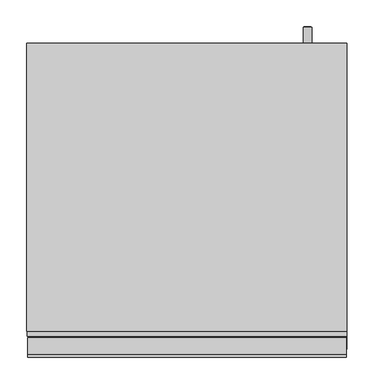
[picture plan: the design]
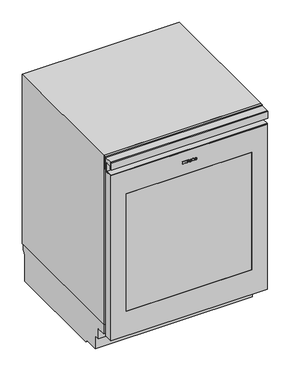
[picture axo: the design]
"""IFC4 building model written with IfcOpenShell, lengths in millimetres: proxy geometry."""

from ifc_helpers import new_model, si_unit, point, frame, frame_2d, origin, origin_with_axes, place, context, project, spatial, polyline, circle_curve, ellipse_curve, trimmed, segment, composite_curve, outline, extrude, faceted_brep, source, transform, mapped, element, save
from ifc_brep_helpers import plane_surface, cylinder_surface, revolved_surface, extruded_surface, advanced_brep


def specialty_equipment_1184f20f(model_context):
    return source(origin(), model_context, "Body", "SolidModel", [
        extrude(outline(polyline([(722.339, -25.038), (722.339, -23.949), (716.318, -23.949), (716.318, -25.038), (714.806, -25.038), (714.806, -21.078), (716.318, -21.078), (716.318, -22.158), (720.1401247, -22.158), (714.806, -18.135), (720.2462223, -14.094), (716.318, -14.094), (716.318, -15.201), (714.806, -15.201), (714.806, -8.019), (716.318, -8.019), (716.318, -9.162), (722.339, -9.162), (722.339, -8.019), (723.806, -8.019), (723.806, -13.5), (720.431, -16.128), (723.806, -18.765), (723.806, -25.038), (722.339, -25.038)])), frame((0.0, -1.0, 0.0), z_axis=(0.0, 1.0, 0.0), x_axis=(0.0, 0.0, 1.0)), (0.0, 0.0, 1.0), 1.0),
        extrude(outline(polyline([(722.339, 11.484), (722.339, 12.564), (716.318, 12.564), (716.318, 11.484), (714.806, 11.484), (714.806, 18.783), (716.318, 18.783), (716.318, 17.676), (723.806, 17.676), (723.806, 11.484), (722.339, 11.484)])), frame((0.0, -1.0, 0.0), z_axis=(0.0, 1.0, 0.0), x_axis=(0.0, 0.0, 1.0)), (0.0, 0.0, 1.0), 1.0),
        extrude(outline(polyline([(723.275, -4.878), (721.817, -4.194), (723.239, -1.143), (724.697, -1.818), (723.275, -4.878)])), frame((0.0, -1.0, 0.0), z_axis=(0.0, 1.0, 0.0), x_axis=(0.0, 0.0, 1.0)), (0.0, 0.0, 1.0), 1.0),
        extrude(outline(polyline([(721.619, -7.101), (720.008, -7.101), (720.008, -6.03), (716.318, -6.03), (716.318, -7.101), (714.806, -7.101), (714.806, 0.0), (716.318, 0.0), (716.318, -1.044), (721.619, -1.044), (721.619, -7.101)])), frame((0.0, -1.0, 0.0), z_axis=(0.0, 1.0, 0.0), x_axis=(0.0, 0.0, 1.0)), (0.0, 0.0, 1.0), 1.0),
        advanced_brep(
        [(4.959, -1.0, 716.939), (4.959, -1.0, 717.848), (10.98, -1.0, 717.848), (0.504, -1.0, 717.848), (2.979, -1.0, 714.806), (10.827, -1.0, 716.939), (8.109, -1.0, 716.939), (5.967, -1.0, 715.931), (4.959, -1.0, 719.0), (4.959, -1.0, 719.981), (6.498, -1.0, 719.981), (6.498, -1.0, 719.0), (4.959, 0.0, 716.939), (5.967, 0.0, 715.931), (8.109, 0.0, 716.939), (10.827, 0.0, 716.939), (2.979, 0.0, 714.806), (0.504, 0.0, 717.848), (10.98, 0.0, 717.848), (4.959, 0.0, 717.848), (4.959, 0.0, 719.0), (6.498, 0.0, 719.0), (6.498, 0.0, 719.981), (4.959, 0.0, 719.981)],
        [
            (0, 1),
            (1, 2),
            (2, 3, ellipse_curve(frame((5.742, -1.0, 717.848), z_axis=(0.0, -1.0, 0.0), x_axis=(-1.0, 0.0, 0.0)), 5.238, 4.329)),
            (3, 4, circle_curve(frame((3.9870491, -1.0, 718.154), z_axis=(0.0, -1.0, 0.0), x_axis=(0.0, 0.0, -1.0)), 3.4964649)),
            (4, 5, circle_curve(frame((5.6371428, -1.0, 720.53), z_axis=(0.0, -1.0, 0.0), x_axis=(0.0, 0.0, -1.0)), 6.3110933)),
            (5, 6),
            (6, 7, circle_curve(frame((6.4069412, -1.0, 717.776), z_axis=(0.0, 1.0, 0.0), x_axis=(0.0, 0.0, -1.0)), 1.896727)),
            (7, 0, circle_curve(frame((5.967, -1.0, 716.939), z_axis=(0.0, 1.0, 0.0), x_axis=(0.0, 0.0, -1.0)), 1.008)),
            (8, 9),
            (9, 10, circle_curve(frame((5.7285, -1.0, 719.981), z_axis=(0.0, 1.0, 0.0), x_axis=(0.0, 0.0, -1.0)), 0.7695)),
            (10, 11),
            (11, 8),
            (12, 13, circle_curve(frame((5.967, 0.0, 716.939), z_axis=(0.0, -1.0, 0.0), x_axis=(0.0, 0.0, -1.0)), 1.008)),
            (13, 14, circle_curve(frame((6.4069412, 0.0, 717.776), z_axis=(0.0, -1.0, 0.0), x_axis=(0.0, 0.0, -1.0)), 1.896727)),
            (14, 15),
            (15, 16, circle_curve(frame((5.6371428, 0.0, 720.53), z_axis=(0.0, 1.0, 0.0), x_axis=(0.0, 0.0, -1.0)), 6.3110933)),
            (16, 17, circle_curve(frame((3.9870491, 0.0, 718.154), z_axis=(0.0, 1.0, 0.0), x_axis=(0.0, 0.0, -1.0)), 3.4964649)),
            (17, 18, ellipse_curve(frame((5.742, 0.0, 717.848), z_axis=(0.0, 1.0, 0.0), x_axis=(-1.0, 0.0, 0.0)), 5.238, 4.329)),
            (18, 19),
            (19, 12),
            (20, 21),
            (21, 22),
            (22, 23, circle_curve(frame((5.7285, 0.0, 719.981), z_axis=(0.0, -1.0, 0.0), x_axis=(0.0, 0.0, -1.0)), 0.7695)),
            (23, 20),
            (0, 12),
            (19, 1),
            (18, 2),
            (5, 15),
            (14, 6),
            (17, 3),
            (13, 7),
            (16, 4),
            (8, 20),
            (23, 9),
            (22, 10),
            (21, 11),
        ],
        [
            plane_surface(frame((4.959, -1.0, 717.848), z_axis=(0.0, -1.0, 0.0), x_axis=(0.0, 0.0, 1.0))),
            plane_surface(frame((4.959, 0.0, 717.848), z_axis=(0.0, 1.0, 0.0), x_axis=(0.0, 0.0, -1.0))),
            plane_surface(frame((4.959, -1.0, 716.939), z_axis=(1.0, 0.0, 0.0), x_axis=(0.0, 1.0, 0.0))),
            plane_surface(frame((4.959, -1.0, 717.848), z_axis=(0.0, 0.0, -1.0), x_axis=(0.0, 1.0, 0.0))),
            plane_surface(frame((10.827, -1.0, 716.939), z_axis=(0.0, 0.0, 1.0), x_axis=(0.0, 1.0, 0.0))),
            extruded_surface(trimmed(ellipse_curve(frame((5.742, 1.0, 717.848), z_axis=(0.0, -1.0, 0.0), x_axis=(-1.0, 0.0, 0.0)), 5.238, 4.329), [point((10.98, 1.0, 717.848))], [point((0.504, 1.0, 717.848))], True, "CARTESIAN"), (0.0, -1.0, 0.0), 1.0),
            revolved_surface(polyline([(6.4069412, 0.0, 715.8792729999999), (6.4069412, -1.0, 715.8792729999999)]), (6.4069412, 0.0, 717.776), (0.0, 1.0, 0.0)),
            revolved_surface(polyline([(5.967, 0.0, 715.9309999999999), (5.967, -1.0, 715.9309999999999)]), (5.967, 0.0, 716.939), (0.0, 1.0, 0.0)),
            cylinder_surface(frame((3.9870491, 0.0, 718.154), z_axis=(0.0, -1.0, 0.0), x_axis=(0.0, 0.0, -1.0)), 3.4964649),
            cylinder_surface(frame((5.6371428, 0.0, 720.53), z_axis=(0.0, -1.0, 0.0), x_axis=(0.0, 0.0, -1.0)), 6.3110933),
            plane_surface(frame((4.959, -1.0, 719.0), z_axis=(1.0, 0.0, 0.0), x_axis=(0.0, 1.0, 0.0))),
            revolved_surface(polyline([(5.7285, 0.0, 719.2115), (5.7285, -1.0, 719.2115)]), (5.7285, 0.0, 719.981), (0.0, 1.0, 0.0)),
            plane_surface(frame((6.498, -1.0, 719.981), z_axis=(-1.0, 0.0, 0.0), x_axis=(0.0, 1.0, 0.0))),
            plane_surface(frame((6.498, -1.0, 719.0), z_axis=(0.0, 0.0, 1.0), x_axis=(0.0, 1.0, 0.0))),
        ],
        [
            (0, [[1, 2, 3, 4, 5, 6, 7, 8], [9, 10, 11, 12]]),
            (1, [[13, 14, 15, 16, 17, 18, 19, 20], [21, 22, 23, 24]]),
            (2, [[-1, 25, -20, 26]]),
            (3, [[-2, -26, -19, 27]]),
            (4, [[-6, 28, -15, 29]]),
            (5, [[-3, -27, -18, 30]]),
            (6, [[-7, -29, -14, 31]]),
            (7, [[-8, -31, -13, -25]]),
            (8, [[-4, -30, -17, 32]]),
            (9, [[-5, -32, -16, -28]]),
            (10, [[-9, 33, -24, 34]]),
            (11, [[-10, -34, -23, 35]]),
            (12, [[-11, -35, -22, 36]]),
            (13, [[-12, -36, -21, -33]]),
        ],
    ),
        advanced_brep(
        [(23.742, -1.0, 716.939), (23.742, -1.0, 717.848), (29.763, -1.0, 717.848), (19.287, -1.0, 717.848), (21.762, -1.0, 714.806), (29.61, -1.0, 716.939), (26.892, -1.0, 716.939), (24.75, -1.0, 715.931), (23.742, -1.0, 719.0), (23.742, -1.0, 719.981), (25.281, -1.0, 719.981), (25.281, -1.0, 719.0), (23.742, 0.0, 716.939), (24.75, 0.0, 715.931), (26.892, 0.0, 716.939), (29.61, 0.0, 716.939), (21.762, 0.0, 714.806), (19.287, 0.0, 717.848), (29.763, 0.0, 717.848), (23.742, 0.0, 717.848), (23.742, 0.0, 719.0), (25.281, 0.0, 719.0), (25.281, 0.0, 719.981), (23.742, 0.0, 719.981)],
        [
            (0, 1),
            (1, 2),
            (2, 3, ellipse_curve(frame((24.525, -1.0, 717.848), z_axis=(0.0, -1.0, 0.0), x_axis=(-1.0, 0.0, 0.0)), 5.238, 4.329)),
            (3, 4, circle_curve(frame((22.7700491, -1.0, 718.154), z_axis=(0.0, -1.0, 0.0), x_axis=(0.0, 0.0, -1.0)), 3.4964649)),
            (4, 5, circle_curve(frame((24.4201428, -1.0, 720.53), z_axis=(0.0, -1.0, 0.0), x_axis=(0.0, 0.0, -1.0)), 6.3110933)),
            (5, 6),
            (6, 7, circle_curve(frame((25.1899412, -1.0, 717.776), z_axis=(0.0, 1.0, 0.0), x_axis=(0.0, 0.0, -1.0)), 1.896727)),
            (7, 0, circle_curve(frame((24.75, -1.0, 716.939), z_axis=(0.0, 1.0, 0.0), x_axis=(0.0, 0.0, -1.0)), 1.008)),
            (8, 9),
            (9, 10, circle_curve(frame((24.5115, -1.0, 719.981), z_axis=(0.0, 1.0, 0.0), x_axis=(0.0, 0.0, -1.0)), 0.7695)),
            (10, 11),
            (11, 8),
            (12, 13, circle_curve(frame((24.75, 0.0, 716.939), z_axis=(0.0, -1.0, 0.0), x_axis=(0.0, 0.0, -1.0)), 1.008)),
            (13, 14, circle_curve(frame((25.1899412, 0.0, 717.776), z_axis=(0.0, -1.0, 0.0), x_axis=(0.0, 0.0, -1.0)), 1.896727)),
            (14, 15),
            (15, 16, circle_curve(frame((24.4201428, 0.0, 720.53), z_axis=(0.0, 1.0, 0.0), x_axis=(0.0, 0.0, -1.0)), 6.3110933)),
            (16, 17, circle_curve(frame((22.7700491, 0.0, 718.154), z_axis=(0.0, 1.0, 0.0), x_axis=(0.0, 0.0, -1.0)), 3.4964649)),
            (17, 18, ellipse_curve(frame((24.525, 0.0, 717.848), z_axis=(0.0, 1.0, 0.0), x_axis=(-1.0, 0.0, 0.0)), 5.238, 4.329)),
            (18, 19),
            (19, 12),
            (20, 21),
            (21, 22),
            (22, 23, circle_curve(frame((24.5115, 0.0, 719.981), z_axis=(0.0, -1.0, 0.0), x_axis=(0.0, 0.0, -1.0)), 0.7695)),
            (23, 20),
            (0, 12),
            (19, 1),
            (18, 2),
            (5, 15),
            (14, 6),
            (17, 3),
            (13, 7),
            (16, 4),
            (8, 20),
            (23, 9),
            (22, 10),
            (21, 11),
        ],
        [
            plane_surface(frame((23.742, -1.0, 717.848), z_axis=(0.0, -1.0, 0.0), x_axis=(0.0, 0.0, 1.0))),
            plane_surface(frame((23.742, 0.0, 717.848), z_axis=(0.0, 1.0, 0.0), x_axis=(0.0, 0.0, -1.0))),
            plane_surface(frame((23.742, -1.0, 716.939), z_axis=(1.0, 0.0, 0.0), x_axis=(0.0, 1.0, 0.0))),
            plane_surface(frame((23.742, -1.0, 717.848), z_axis=(0.0, 0.0, -1.0), x_axis=(0.0, 1.0, 0.0))),
            plane_surface(frame((29.61, -1.0, 716.939), z_axis=(0.0, 0.0, 1.0), x_axis=(0.0, 1.0, 0.0))),
            extruded_surface(trimmed(ellipse_curve(frame((24.525, 1.0, 717.848), z_axis=(0.0, -1.0, 0.0), x_axis=(-1.0, 0.0, 0.0)), 5.238, 4.329), [point((29.763, 1.0, 717.848))], [point((19.287, 1.0, 717.848))], True, "CARTESIAN"), (0.0, -1.0, 0.0), 1.0),
            revolved_surface(polyline([(25.1899412, 0.0, 715.8792729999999), (25.1899412, -1.0, 715.8792729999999)]), (25.1899412, 0.0, 717.776), (0.0, 1.0, 0.0)),
            revolved_surface(polyline([(24.75, 0.0, 715.9309999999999), (24.75, -1.0, 715.9309999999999)]), (24.75, 0.0, 716.939), (0.0, 1.0, 0.0)),
            cylinder_surface(frame((22.7700491, 0.0, 718.154), z_axis=(0.0, -1.0, 0.0), x_axis=(0.0, 0.0, -1.0)), 3.4964649),
            cylinder_surface(frame((24.4201428, 0.0, 720.53), z_axis=(0.0, -1.0, 0.0), x_axis=(0.0, 0.0, -1.0)), 6.3110933),
            plane_surface(frame((23.742, -1.0, 719.0), z_axis=(1.0, 0.0, 0.0), x_axis=(0.0, 1.0, 0.0))),
            revolved_surface(polyline([(24.5115, 0.0, 719.2115), (24.5115, -1.0, 719.2115)]), (24.5115, 0.0, 719.981), (0.0, 1.0, 0.0)),
            plane_surface(frame((25.281, -1.0, 719.981), z_axis=(-1.0, 0.0, 0.0), x_axis=(0.0, 1.0, 0.0))),
            plane_surface(frame((25.281, -1.0, 719.0), z_axis=(0.0, 0.0, 1.0), x_axis=(0.0, 1.0, 0.0))),
        ],
        [
            (0, [[1, 2, 3, 4, 5, 6, 7, 8], [9, 10, 11, 12]]),
            (1, [[13, 14, 15, 16, 17, 18, 19, 20], [21, 22, 23, 24]]),
            (2, [[-1, 25, -20, 26]]),
            (3, [[-2, -26, -19, 27]]),
            (4, [[-6, 28, -15, 29]]),
            (5, [[-3, -27, -18, 30]]),
            (6, [[-7, -29, -14, 31]]),
            (7, [[-8, -31, -13, -25]]),
            (8, [[-4, -30, -17, 32]]),
            (9, [[-5, -32, -16, -28]]),
            (10, [[-9, 33, -24, 34]]),
            (11, [[-10, -34, -23, 35]]),
            (12, [[-11, -35, -22, 36]]),
            (13, [[-12, -36, -21, -33]]),
        ],
    ),
        extrude(outline(polyline([(699.491, -85.038), (699.491, -83.949), (693.47, -83.949), (693.47, -85.038), (691.958, -85.038), (691.958, -81.078), (693.47, -81.078), (693.47, -82.158), (697.2921247, -82.158), (691.958, -78.135), (697.3982223, -74.094), (693.47, -74.094), (693.47, -75.201), (691.958, -75.201), (691.958, -68.019), (693.47, -68.019), (693.47, -69.162), (699.491, -69.162), (699.491, -68.019), (700.958, -68.019), (700.958, -73.5), (697.583, -76.128), (700.958, -78.765), (700.958, -85.038), (699.491, -85.038)])), frame((0.0, 50.0, 0.0), z_axis=(0.0, 1.0, 0.0), x_axis=(0.0, 0.0, 1.0)), (0.0, 0.0, 1.0), 1.0),
        extrude(outline(polyline([(699.491, -48.516), (699.491, -47.436), (693.47, -47.436), (693.47, -48.516), (691.958, -48.516), (691.958, -41.217), (693.47, -41.217), (693.47, -42.324), (700.958, -42.324), (700.958, -48.516), (699.491, -48.516)])), frame((0.0, 50.0, 0.0), z_axis=(0.0, 1.0, 0.0), x_axis=(0.0, 0.0, 1.0)), (0.0, 0.0, 1.0), 1.0),
        extrude(outline(polyline([(700.427, -64.878), (698.969, -64.194), (700.391, -61.143), (701.849, -61.818), (700.427, -64.878)])), frame((0.0, 50.0, 0.0), z_axis=(0.0, 1.0, 0.0), x_axis=(0.0, 0.0, 1.0)), (0.0, 0.0, 1.0), 1.0),
        extrude(outline(polyline([(698.771, -67.101), (697.16, -67.101), (697.16, -66.03), (693.47, -66.03), (693.47, -67.101), (691.958, -67.101), (691.958, -60.0), (693.47, -60.0), (693.47, -61.044), (698.771, -61.044), (698.771, -67.101)])), frame((0.0, 50.0, 0.0), z_axis=(0.0, 1.0, 0.0), x_axis=(0.0, 0.0, 1.0)), (0.0, 0.0, 1.0), 1.0),
        advanced_brep(
        [(-55.041, 50.0, 694.091), (-55.041, 50.0, 695.0), (-49.02, 50.0, 695.0), (-59.496, 50.0, 695.0), (-57.021, 50.0, 691.958), (-49.173, 50.0, 694.091), (-51.891, 50.0, 694.091), (-54.033, 50.0, 693.083), (-55.041, 50.0, 696.152), (-55.041, 50.0, 697.133), (-53.502, 50.0, 697.133), (-53.502, 50.0, 696.152), (-55.041, 51.0, 694.091), (-54.033, 51.0, 693.083), (-51.891, 51.0, 694.091), (-49.173, 51.0, 694.091), (-57.021, 51.0, 691.958), (-59.496, 51.0, 695.0), (-49.02, 51.0, 695.0), (-55.041, 51.0, 695.0), (-55.041, 51.0, 696.152), (-53.502, 51.0, 696.152), (-53.502, 51.0, 697.133), (-55.041, 51.0, 697.133)],
        [
            (0, 1),
            (1, 2),
            (2, 3, ellipse_curve(frame((-54.258, 50.0, 695.0), z_axis=(0.0, -1.0, 0.0), x_axis=(-1.0, 0.0, 0.0)), 5.238, 4.329)),
            (3, 4, circle_curve(frame((-56.0129509, 50.0, 695.306), z_axis=(0.0, -1.0, 0.0), x_axis=(0.0, 0.0, -1.0)), 3.4964649)),
            (4, 5, circle_curve(frame((-54.3628572, 50.0, 697.682), z_axis=(0.0, -1.0, 0.0), x_axis=(0.0, 0.0, -1.0)), 6.3110933)),
            (5, 6),
            (6, 7, circle_curve(frame((-53.5930588, 50.0, 694.928), z_axis=(0.0, 1.0, 0.0), x_axis=(0.0, 0.0, -1.0)), 1.896727)),
            (7, 0, circle_curve(frame((-54.033, 50.0, 694.091), z_axis=(0.0, 1.0, 0.0), x_axis=(0.0, 0.0, -1.0)), 1.008)),
            (8, 9),
            (9, 10, circle_curve(frame((-54.2715, 50.0, 697.133), z_axis=(0.0, 1.0, 0.0), x_axis=(0.0, 0.0, -1.0)), 0.7695)),
            (10, 11),
            (11, 8),
            (12, 13, circle_curve(frame((-54.033, 51.0, 694.091), z_axis=(0.0, -1.0, 0.0), x_axis=(0.0, 0.0, -1.0)), 1.008)),
            (13, 14, circle_curve(frame((-53.5930588, 51.0, 694.928), z_axis=(0.0, -1.0, 0.0), x_axis=(0.0, 0.0, -1.0)), 1.896727)),
            (14, 15),
            (15, 16, circle_curve(frame((-54.3628572, 51.0, 697.682), z_axis=(0.0, 1.0, 0.0), x_axis=(0.0, 0.0, -1.0)), 6.3110933)),
            (16, 17, circle_curve(frame((-56.0129509, 51.0, 695.306), z_axis=(0.0, 1.0, 0.0), x_axis=(0.0, 0.0, -1.0)), 3.4964649)),
            (17, 18, ellipse_curve(frame((-54.258, 51.0, 695.0), z_axis=(0.0, 1.0, 0.0), x_axis=(-1.0, 0.0, 0.0)), 5.238, 4.329)),
            (18, 19),
            (19, 12),
            (20, 21),
            (21, 22),
            (22, 23, circle_curve(frame((-54.2715, 51.0, 697.133), z_axis=(0.0, -1.0, 0.0), x_axis=(0.0, 0.0, -1.0)), 0.7695)),
            (23, 20),
            (0, 12),
            (19, 1),
            (18, 2),
            (5, 15),
            (14, 6),
            (17, 3),
            (13, 7),
            (16, 4),
            (8, 20),
            (23, 9),
            (22, 10),
            (21, 11),
        ],
        [
            plane_surface(frame((-55.041, 50.0, 695.0), z_axis=(0.0, -1.0, 0.0), x_axis=(0.0, 0.0, 1.0))),
            plane_surface(frame((-55.041, 51.0, 695.0), z_axis=(0.0, 1.0, 0.0), x_axis=(0.0, 0.0, -1.0))),
            plane_surface(frame((-55.041, 50.0, 694.091), z_axis=(1.0, 0.0, 0.0), x_axis=(0.0, 1.0, 0.0))),
            plane_surface(frame((-55.041, 50.0, 695.0), z_axis=(0.0, 0.0, -1.0), x_axis=(0.0, 1.0, 0.0))),
            plane_surface(frame((-49.173, 50.0, 694.091), z_axis=(0.0, 0.0, 1.0), x_axis=(0.0, 1.0, 0.0))),
            extruded_surface(trimmed(ellipse_curve(frame((-54.258, 52.0, 695.0), z_axis=(0.0, -1.0, 0.0), x_axis=(-1.0, 0.0, 0.0)), 5.238, 4.329), [point((-49.02, 52.0, 695.0))], [point((-59.496, 52.0, 695.0))], True, "CARTESIAN"), (0.0, -1.0, 0.0), 1.0),
            revolved_surface(polyline([(-53.5930588, 51.0, 693.0312729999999), (-53.5930588, 50.0, 693.0312729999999)]), (-53.5930588, 51.0, 694.928), (0.0, 1.0, 0.0)),
            revolved_surface(polyline([(-54.033, 51.0, 693.083), (-54.033, 50.0, 693.083)]), (-54.033, 51.0, 694.091), (0.0, 1.0, 0.0)),
            cylinder_surface(frame((-56.0129509, 51.0, 695.306), z_axis=(0.0, -1.0, 0.0), x_axis=(0.0, 0.0, -1.0)), 3.4964649),
            cylinder_surface(frame((-54.3628572, 51.0, 697.682), z_axis=(0.0, -1.0, 0.0), x_axis=(0.0, 0.0, -1.0)), 6.3110933),
            plane_surface(frame((-55.041, 50.0, 696.152), z_axis=(1.0, 0.0, 0.0), x_axis=(0.0, 1.0, 0.0))),
            revolved_surface(polyline([(-54.2715, 51.0, 696.3635), (-54.2715, 50.0, 696.3635)]), (-54.2715, 51.0, 697.133), (0.0, 1.0, 0.0)),
            plane_surface(frame((-53.502, 50.0, 697.133), z_axis=(-1.0, 0.0, 0.0), x_axis=(0.0, 1.0, 0.0))),
            plane_surface(frame((-53.502, 50.0, 696.152), z_axis=(0.0, 0.0, 1.0), x_axis=(0.0, 1.0, 0.0))),
        ],
        [
            (0, [[1, 2, 3, 4, 5, 6, 7, 8], [9, 10, 11, 12]]),
            (1, [[13, 14, 15, 16, 17, 18, 19, 20], [21, 22, 23, 24]]),
            (2, [[-1, 25, -20, 26]]),
            (3, [[-2, -26, -19, 27]]),
            (4, [[-6, 28, -15, 29]]),
            (5, [[-3, -27, -18, 30]]),
            (6, [[-7, -29, -14, 31]]),
            (7, [[-8, -31, -13, -25]]),
            (8, [[-4, -30, -17, 32]]),
            (9, [[-5, -32, -16, -28]]),
            (10, [[-9, 33, -24, 34]]),
            (11, [[-10, -34, -23, 35]]),
            (12, [[-11, -35, -22, 36]]),
            (13, [[-12, -36, -21, -33]]),
        ],
    ),
        advanced_brep(
        [(-36.258, 50.0, 694.091), (-36.258, 50.0, 695.0), (-30.237, 50.0, 695.0), (-40.713, 50.0, 695.0), (-38.238, 50.0, 691.958), (-30.39, 50.0, 694.091), (-33.108, 50.0, 694.091), (-35.25, 50.0, 693.083), (-36.258, 50.0, 696.152), (-36.258, 50.0, 697.133), (-34.719, 50.0, 697.133), (-34.719, 50.0, 696.152), (-36.258, 51.0, 694.091), (-35.25, 51.0, 693.083), (-33.108, 51.0, 694.091), (-30.39, 51.0, 694.091), (-38.238, 51.0, 691.958), (-40.713, 51.0, 695.0), (-30.237, 51.0, 695.0), (-36.258, 51.0, 695.0), (-36.258, 51.0, 696.152), (-34.719, 51.0, 696.152), (-34.719, 51.0, 697.133), (-36.258, 51.0, 697.133)],
        [
            (0, 1),
            (1, 2),
            (2, 3, ellipse_curve(frame((-35.475, 50.0, 695.0), z_axis=(0.0, -1.0, 0.0), x_axis=(-1.0, 0.0, 0.0)), 5.238, 4.329)),
            (3, 4, circle_curve(frame((-37.2299509, 50.0, 695.306), z_axis=(0.0, -1.0, 0.0), x_axis=(0.0, 0.0, -1.0)), 3.4964649)),
            (4, 5, circle_curve(frame((-35.5798572, 50.0, 697.682), z_axis=(0.0, -1.0, 0.0), x_axis=(0.0, 0.0, -1.0)), 6.3110933)),
            (5, 6),
            (6, 7, circle_curve(frame((-34.8100588, 50.0, 694.928), z_axis=(0.0, 1.0, 0.0), x_axis=(0.0, 0.0, -1.0)), 1.896727)),
            (7, 0, circle_curve(frame((-35.25, 50.0, 694.091), z_axis=(0.0, 1.0, 0.0), x_axis=(0.0, 0.0, -1.0)), 1.008)),
            (8, 9),
            (9, 10, circle_curve(frame((-35.4885, 50.0, 697.133), z_axis=(0.0, 1.0, 0.0), x_axis=(0.0, 0.0, -1.0)), 0.7695)),
            (10, 11),
            (11, 8),
            (12, 13, circle_curve(frame((-35.25, 51.0, 694.091), z_axis=(0.0, -1.0, 0.0), x_axis=(0.0, 0.0, -1.0)), 1.008)),
            (13, 14, circle_curve(frame((-34.8100588, 51.0, 694.928), z_axis=(0.0, -1.0, 0.0), x_axis=(0.0, 0.0, -1.0)), 1.896727)),
            (14, 15),
            (15, 16, circle_curve(frame((-35.5798572, 51.0, 697.682), z_axis=(0.0, 1.0, 0.0), x_axis=(0.0, 0.0, -1.0)), 6.3110933)),
            (16, 17, circle_curve(frame((-37.2299509, 51.0, 695.306), z_axis=(0.0, 1.0, 0.0), x_axis=(0.0, 0.0, -1.0)), 3.4964649)),
            (17, 18, ellipse_curve(frame((-35.475, 51.0, 695.0), z_axis=(0.0, 1.0, 0.0), x_axis=(-1.0, 0.0, 0.0)), 5.238, 4.329)),
            (18, 19),
            (19, 12),
            (20, 21),
            (21, 22),
            (22, 23, circle_curve(frame((-35.4885, 51.0, 697.133), z_axis=(0.0, -1.0, 0.0), x_axis=(0.0, 0.0, -1.0)), 0.7695)),
            (23, 20),
            (0, 12),
            (19, 1),
            (18, 2),
            (5, 15),
            (14, 6),
            (17, 3),
            (13, 7),
            (16, 4),
            (8, 20),
            (23, 9),
            (22, 10),
            (21, 11),
        ],
        [
            plane_surface(frame((-36.258, 50.0, 695.0), z_axis=(0.0, -1.0, 0.0), x_axis=(0.0, 0.0, 1.0))),
            plane_surface(frame((-36.258, 51.0, 695.0), z_axis=(0.0, 1.0, 0.0), x_axis=(0.0, 0.0, -1.0))),
            plane_surface(frame((-36.258, 50.0, 694.091), z_axis=(1.0, 0.0, 0.0), x_axis=(0.0, 1.0, 0.0))),
            plane_surface(frame((-36.258, 50.0, 695.0), z_axis=(0.0, 0.0, -1.0), x_axis=(0.0, 1.0, 0.0))),
            plane_surface(frame((-30.39, 50.0, 694.091), z_axis=(0.0, 0.0, 1.0), x_axis=(0.0, 1.0, 0.0))),
            extruded_surface(trimmed(ellipse_curve(frame((-35.475, 52.0, 695.0), z_axis=(0.0, -1.0, 0.0), x_axis=(-1.0, 0.0, 0.0)), 5.238, 4.329), [point((-30.237, 52.0, 695.0))], [point((-40.713, 52.0, 695.0))], True, "CARTESIAN"), (0.0, -1.0, 0.0), 1.0),
            revolved_surface(polyline([(-34.8100588, 51.0, 693.0312729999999), (-34.8100588, 50.0, 693.0312729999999)]), (-34.8100588, 51.0, 694.928), (0.0, 1.0, 0.0)),
            revolved_surface(polyline([(-35.25, 51.0, 693.083), (-35.25, 50.0, 693.083)]), (-35.25, 51.0, 694.091), (0.0, 1.0, 0.0)),
            cylinder_surface(frame((-37.2299509, 51.0, 695.306), z_axis=(0.0, -1.0, 0.0), x_axis=(0.0, 0.0, -1.0)), 3.4964649),
            cylinder_surface(frame((-35.5798572, 51.0, 697.682), z_axis=(0.0, -1.0, 0.0), x_axis=(0.0, 0.0, -1.0)), 6.3110933),
            plane_surface(frame((-36.258, 50.0, 696.152), z_axis=(1.0, 0.0, 0.0), x_axis=(0.0, 1.0, 0.0))),
            revolved_surface(polyline([(-35.4885, 51.0, 696.3635), (-35.4885, 50.0, 696.3635)]), (-35.4885, 51.0, 697.133), (0.0, 1.0, 0.0)),
            plane_surface(frame((-34.719, 50.0, 697.133), z_axis=(-1.0, 0.0, 0.0), x_axis=(0.0, 1.0, 0.0))),
            plane_surface(frame((-34.719, 50.0, 696.152), z_axis=(0.0, 0.0, 1.0), x_axis=(0.0, 1.0, 0.0))),
        ],
        [
            (0, [[1, 2, 3, 4, 5, 6, 7, 8], [9, 10, 11, 12]]),
            (1, [[13, 14, 15, 16, 17, 18, 19, 20], [21, 22, 23, 24]]),
            (2, [[-1, 25, -20, 26]]),
            (3, [[-2, -26, -19, 27]]),
            (4, [[-6, 28, -15, 29]]),
            (5, [[-3, -27, -18, 30]]),
            (6, [[-7, -29, -14, 31]]),
            (7, [[-8, -31, -13, -25]]),
            (8, [[-4, -30, -17, 32]]),
            (9, [[-5, -32, -16, -28]]),
            (10, [[-9, 33, -24, 34]]),
            (11, [[-10, -34, -23, 35]]),
            (12, [[-11, -35, -22, 36]]),
            (13, [[-12, -36, -21, -33]]),
        ],
    ),
        extrude(outline(polyline([(567.7947388, -157.5), (572.5, -157.5), (576.5, -161.5), (576.5, -168.5), (572.5, -172.5), (567.7947388, -172.5), (567.7947388, -157.5)])), frame((0.0, 54.5000244, 0.0), z_axis=(0.0, 1.0, 0.0), x_axis=(0.0, 0.0, 1.0)), (0.0, 0.0, 1.0), 433.111792),
        extrude(outline(polyline([(567.7947388, -102.5), (572.5, -102.5), (576.5, -106.5), (576.5, -113.5), (572.5, -117.5), (567.7947388, -117.5), (567.7947388, -102.5)])), frame((0.0, 54.5000244, 0.0), z_axis=(0.0, 1.0, 0.0), x_axis=(0.0, 0.0, 1.0)), (0.0, 0.0, 1.0), 433.111792),
        extrude(outline(polyline([(567.7947388, 157.5), (567.7947388, 172.5), (572.5, 172.5), (576.5, 168.5), (576.5, 161.5), (572.5, 157.5), (567.7947388, 157.5)])), frame((0.0, 54.5000244, 0.0), z_axis=(0.0, 1.0, 0.0), x_axis=(0.0, 0.0, 1.0)), (0.0, 0.0, 1.0), 433.111792),
        extrude(outline(polyline([(567.7947388, 102.5), (567.7947388, 117.5), (572.5, 117.5), (576.5, 113.5), (576.5, 106.5), (572.5, 102.5), (567.7947388, 102.5)])), frame((0.0, 54.5000244, 0.0), z_axis=(0.0, 1.0, 0.0), x_axis=(0.0, 0.0, 1.0)), (0.0, 0.0, 1.0), 433.111792),
        extrude(outline(polyline([(567.7947388, -47.5), (572.5, -47.5), (576.5, -51.5), (576.5, -58.5), (572.5, -62.5), (567.7947388, -62.5), (567.7947388, -47.5)])), frame((0.0, 54.5000244, 0.0), z_axis=(0.0, 1.0, 0.0), x_axis=(0.0, 0.0, 1.0)), (0.0, 0.0, 1.0), 433.111792),
        extrude(outline(polyline([(567.7947388, 47.5), (567.7947388, 62.5), (572.5, 62.5), (576.5, 58.5), (576.5, 51.5), (572.5, 47.5), (567.7947388, 47.5)])), frame((0.0, 54.5000244, 0.0), z_axis=(0.0, 1.0, 0.0), x_axis=(0.0, 0.0, 1.0)), (0.0, 0.0, 1.0), 433.111792),
        extrude(outline(polyline([(567.7947388, 7.5), (572.5, 7.5), (576.5, 3.5), (576.5, -3.5), (572.5, -7.5), (567.7947388, -7.5), (567.7947388, 7.5)])), frame((0.0, 54.5000244, 0.0), z_axis=(0.0, 1.0, 0.0), x_axis=(0.0, 0.0, 1.0)), (0.0, 0.0, 1.0), 433.111792),
        extrude(outline(polyline([(478.3, -157.5), (483.0052612, -157.5), (487.0052612, -161.5), (487.0052612, -168.5), (483.0052612, -172.5), (478.3, -172.5), (478.3, -157.5)])), frame((0.0, 54.5000244, 0.0), z_axis=(0.0, 1.0, 0.0), x_axis=(0.0, 0.0, 1.0)), (0.0, 0.0, 1.0), 433.111792),
        extrude(outline(polyline([(478.3, -102.5), (483.0052612, -102.5), (487.0052612, -106.5), (487.0052612, -113.5), (483.0052612, -117.5), (478.3, -117.5), (478.3, -102.5)])), frame((0.0, 54.5000244, 0.0), z_axis=(0.0, 1.0, 0.0), x_axis=(0.0, 0.0, 1.0)), (0.0, 0.0, 1.0), 433.111792),
        extrude(outline(polyline([(478.3, 157.5), (478.3, 172.5), (483.0052612, 172.5), (487.0052612, 168.5), (487.0052612, 161.5), (483.0052612, 157.5), (478.3, 157.5)])), frame((0.0, 54.5000244, 0.0), z_axis=(0.0, 1.0, 0.0), x_axis=(0.0, 0.0, 1.0)), (0.0, 0.0, 1.0), 433.111792),
        extrude(outline(polyline([(478.3, 102.5), (478.3, 117.5), (483.0052612, 117.5), (487.0052612, 113.5), (487.0052612, 106.5), (483.0052612, 102.5), (478.3, 102.5)])), frame((0.0, 54.5000244, 0.0), z_axis=(0.0, 1.0, 0.0), x_axis=(0.0, 0.0, 1.0)), (0.0, 0.0, 1.0), 433.111792),
        extrude(outline(polyline([(478.3, -47.5), (483.0052612, -47.5), (487.0052612, -51.5), (487.0052612, -58.5), (483.0052612, -62.5), (478.3, -62.5), (478.3, -47.5)])), frame((0.0, 54.5000244, 0.0), z_axis=(0.0, 1.0, 0.0), x_axis=(0.0, 0.0, 1.0)), (0.0, 0.0, 1.0), 433.111792),
        extrude(outline(polyline([(478.3, 47.5), (478.3, 62.5), (483.0052612, 62.5), (487.0052612, 58.5), (487.0052612, 51.5), (483.0052612, 47.5), (478.3, 47.5)])), frame((0.0, 54.5000244, 0.0), z_axis=(0.0, 1.0, 0.0), x_axis=(0.0, 0.0, 1.0)), (0.0, 0.0, 1.0), 433.111792),
        extrude(outline(polyline([(478.3, 7.5), (483.0052612, 7.5), (487.0052612, 3.5), (487.0052612, -3.5), (483.0052612, -7.5), (478.3, -7.5), (478.3, 7.5)])), frame((0.0, 54.5000244, 0.0), z_axis=(0.0, 1.0, 0.0), x_axis=(0.0, 0.0, 1.0)), (0.0, 0.0, 1.0), 433.111792),
        extrude(outline(polyline([(387.8, -157.5), (392.5052612, -157.5), (396.5052612, -161.5), (396.5052612, -168.5), (392.5052612, -172.5), (387.8, -172.5), (387.8, -157.5)])), frame((0.0, 54.5000244, 0.0), z_axis=(0.0, 1.0, 0.0), x_axis=(0.0, 0.0, 1.0)), (0.0, 0.0, 1.0), 433.111792),
        extrude(outline(polyline([(387.8, -102.5), (392.5052612, -102.5), (396.5052612, -106.5), (396.5052612, -113.5), (392.5052612, -117.5), (387.8, -117.5), (387.8, -102.5)])), frame((0.0, 54.5000244, 0.0), z_axis=(0.0, 1.0, 0.0), x_axis=(0.0, 0.0, 1.0)), (0.0, 0.0, 1.0), 433.111792),
        extrude(outline(polyline([(387.8, 157.5), (387.8, 172.5), (392.5052612, 172.5), (396.5052612, 168.5), (396.5052612, 161.5), (392.5052612, 157.5), (387.8, 157.5)])), frame((0.0, 54.5000244, 0.0), z_axis=(0.0, 1.0, 0.0), x_axis=(0.0, 0.0, 1.0)), (0.0, 0.0, 1.0), 433.111792),
        extrude(outline(polyline([(387.8, 102.5), (387.8, 117.5), (392.5052612, 117.5), (396.5052612, 113.5), (396.5052612, 106.5), (392.5052612, 102.5), (387.8, 102.5)])), frame((0.0, 54.5000244, 0.0), z_axis=(0.0, 1.0, 0.0), x_axis=(0.0, 0.0, 1.0)), (0.0, 0.0, 1.0), 433.111792),
        extrude(outline(polyline([(387.8, -47.5), (392.5052612, -47.5), (396.5052612, -51.5), (396.5052612, -58.5), (392.5052612, -62.5), (387.8, -62.5), (387.8, -47.5)])), frame((0.0, 54.5000244, 0.0), z_axis=(0.0, 1.0, 0.0), x_axis=(0.0, 0.0, 1.0)), (0.0, 0.0, 1.0), 433.111792),
        extrude(outline(polyline([(387.8, 47.5), (387.8, 62.5), (392.5052612, 62.5), (396.5052612, 58.5), (396.5052612, 51.5), (392.5052612, 47.5), (387.8, 47.5)])), frame((0.0, 54.5000244, 0.0), z_axis=(0.0, 1.0, 0.0), x_axis=(0.0, 0.0, 1.0)), (0.0, 0.0, 1.0), 433.111792),
        extrude(outline(polyline([(387.8, 7.5), (392.5052612, 7.5), (396.5052612, 3.5), (396.5052612, -3.5), (392.5052612, -7.5), (387.8, -7.5), (387.8, 7.5)])), frame((0.0, 54.5000244, 0.0), z_axis=(0.0, 1.0, 0.0), x_axis=(0.0, 0.0, 1.0)), (0.0, 0.0, 1.0), 433.111792),
        extrude(outline(polyline([(238.8, -157.5), (243.5052612, -157.5), (247.5052612, -161.5), (247.5052612, -168.5), (243.5052612, -172.5), (238.8, -172.5), (238.8, -157.5)])), frame((0.0, 54.5000244, 0.0), z_axis=(0.0, 1.0, 0.0), x_axis=(0.0, 0.0, 1.0)), (0.0, 0.0, 1.0), 433.111792),
        extrude(outline(polyline([(238.8, -102.5), (243.5052612, -102.5), (247.5052612, -106.5), (247.5052612, -113.5), (243.5052612, -117.5), (238.8, -117.5), (238.8, -102.5)])), frame((0.0, 54.5000244, 0.0), z_axis=(0.0, 1.0, 0.0), x_axis=(0.0, 0.0, 1.0)), (0.0, 0.0, 1.0), 433.111792),
        extrude(outline(polyline([(238.8, 157.5), (238.8, 172.5), (243.5052612, 172.5), (247.5052612, 168.5), (247.5052612, 161.5), (243.5052612, 157.5), (238.8, 157.5)])), frame((0.0, 54.5000244, 0.0), z_axis=(0.0, 1.0, 0.0), x_axis=(0.0, 0.0, 1.0)), (0.0, 0.0, 1.0), 433.111792),
        extrude(outline(polyline([(238.8, 102.5), (238.8, 117.5), (243.5052612, 117.5), (247.5052612, 113.5), (247.5052612, 106.5), (243.5052612, 102.5), (238.8, 102.5)])), frame((0.0, 54.5000244, 0.0), z_axis=(0.0, 1.0, 0.0), x_axis=(0.0, 0.0, 1.0)), (0.0, 0.0, 1.0), 433.111792),
        extrude(outline(polyline([(238.8, -47.5), (243.5052612, -47.5), (247.5052612, -51.5), (247.5052612, -58.5), (243.5052612, -62.5), (238.8, -62.5), (238.8, -47.5)])), frame((0.0, 54.5000244, 0.0), z_axis=(0.0, 1.0, 0.0), x_axis=(0.0, 0.0, 1.0)), (0.0, 0.0, 1.0), 433.111792),
        extrude(outline(polyline([(238.8, 47.5), (238.8, 62.5), (243.5052612, 62.5), (247.5052612, 58.5), (247.5052612, 51.5), (243.5052612, 47.5), (238.8, 47.5)])), frame((0.0, 54.5000244, 0.0), z_axis=(0.0, 1.0, 0.0), x_axis=(0.0, 0.0, 1.0)), (0.0, 0.0, 1.0), 433.111792),
        extrude(outline(polyline([(238.8, 7.5), (243.5052612, 7.5), (247.5052612, 3.5), (247.5052612, -3.5), (243.5052612, -7.5), (238.8, -7.5), (238.8, 7.5)])), frame((0.0, 54.5000244, 0.0), z_axis=(0.0, 1.0, 0.0), x_axis=(0.0, 0.0, 1.0)), (0.0, 0.0, 1.0), 433.111792),
        extrude(outline(polyline([(238.5, 51.0000244), (-238.5, 51.0000244), (-238.5, 54.5000244), (238.5, 54.5000244), (238.5, 51.0000244)])), frame((0.0, 0.0, 146.0), z_axis=(0.0, 0.0, 1.0), x_axis=(1.0, 0.0, 0.0)), (0.0, 0.0, 1.0), 27.5),
        extrude(outline(polyline([(238.5, 51.0000244), (-238.5, 51.0000244), (-238.5, 54.5000244), (238.5, 54.5000244), (238.5, 51.0000244)])), frame((0.0, 0.0, 235.0), z_axis=(0.0, 0.0, 1.0), x_axis=(1.0, 0.0, 0.0)), (0.0, 0.0, 1.0), 27.5),
        extrude(outline(polyline([(209.0, -226.9226475), (209.0, -238.5), (141.0206134, -238.5), (141.0206134, -216.8069153), (191.4790485, -216.8069153), (209.0, -226.9226475)])), frame((0.0, 54.5000244, 0.0), z_axis=(0.0, 1.0, 0.0), x_axis=(0.0, 0.0, 1.0)), (0.0, 0.0, 1.0), 308.1981801),
        extrude(outline(polyline([(209.0, 226.9226475), (191.4790485, 216.8069153), (141.0206134, 216.8069153), (141.0206134, 238.5), (209.0, 238.5), (209.0, 226.9226475)])), frame((0.0, 54.5000244, 0.0), z_axis=(0.0, 1.0, 0.0), x_axis=(0.0, 0.0, 1.0)), (0.0, 0.0, 1.0), 308.1981801),
        extrude(outline(polyline([(238.5, 51.0000244), (-238.5, 51.0000244), (-238.5, 54.5000244), (238.5, 54.5000244), (238.5, 51.0000244)])), frame((0.0, 0.0, 564.0), z_axis=(0.0, 0.0, 1.0), x_axis=(1.0, 0.0, 0.0)), (0.0, 0.0, 1.0), 27.5),
        extrude(outline(polyline([(238.5, 51.0000244), (-238.5, 51.0000244), (-238.5, 54.5000244), (238.5, 54.5000244), (238.5, 51.0000244)])), frame((0.0, 0.0, 474.5), z_axis=(0.0, 0.0, 1.0), x_axis=(1.0, 0.0, 0.0)), (0.0, 0.0, 1.0), 27.5),
        extrude(outline(polyline([(238.5, 51.0000244), (-238.5, 51.0000244), (-238.5, 54.5000244), (238.5, 54.5000244), (238.5, 51.0000244)])), frame((0.0, 0.0, 384.0), z_axis=(0.0, 0.0, 1.0), x_axis=(1.0, 0.0, 0.0)), (0.0, 0.0, 1.0), 27.5),
        faceted_brep([(250.0, 51.0000244, 719.0), (-250.0, 51.0000244, 719.0), (-250.0, 51.0000244, 665.5838574), (250.0, 51.0000244, 665.5838574), (24.4663125, 51.0000244, 676.4573822), (-24.4663125, 51.0000244, 676.4573822), (-24.4663125, 51.0000244, 712.8698491), (24.4663125, 51.0000244, 712.8698491), (250.0, 487.6118164, 719.0), (250.0, 487.6118164, 665.5838574), (-250.0, 487.6118164, 665.5838574), (-250.0, 487.6118164, 719.0), (24.4663125, 80.5000244, 676.4573822), (24.4663125, 80.5000244, 712.8698491), (-24.4663125, 80.5000244, 712.8698491), (-24.4663125, 80.5000244, 676.4573822)], [[[0, 1, 2, 3], [4, 5, 6, 7]], [[8, 9, 10, 11]], [[1, 0, 8, 11]], [[2, 1, 11, 10]], [[3, 2, 10, 9]], [[0, 3, 9, 8]], [[12, 13, 14, 15]], [[12, 15, 5, 4]], [[15, 14, 6, 5]], [[14, 13, 7, 6]], [[13, 12, 4, 7]]]),
        extrude(outline(polyline([(238.5, 487.6118164), (-238.5, 487.6118164), (-238.5, 491.1118408), (238.5, 491.1118408), (238.5, 487.6118164)])), frame((0.0, 0.0, 474.5), z_axis=(0.0, 0.0, 1.0), x_axis=(1.0, 0.0, 0.0)), (0.0, 0.0, 1.0), 27.5),
        extrude(outline(polyline([(238.5, 487.6118164), (-238.5, 487.6118164), (-238.5, 491.1118408), (238.5, 491.1118408), (238.5, 487.6118164)])), frame((0.0, 0.0, 235.0), z_axis=(0.0, 0.0, 1.0), x_axis=(1.0, 0.0, 0.0)), (0.0, 0.0, 1.0), 27.5),
        extrude(outline(polyline([(238.5, 487.6118164), (-238.5, 487.6118164), (-238.5, 491.1118408), (238.5, 491.1118408), (238.5, 487.6118164)])), frame((0.0, 0.0, 564.0), z_axis=(0.0, 0.0, 1.0), x_axis=(1.0, 0.0, 0.0)), (0.0, 0.0, 1.0), 27.5),
        extrude(outline(polyline([(238.5, 51.0000244), (-238.5, 51.0000244), (-238.5, 54.5000244), (238.5, 54.5000244), (238.5, 51.0000244)])), frame((0.0, 0.0, 235.0), z_axis=(0.0, 0.0, 1.0), x_axis=(1.0, 0.0, 0.0)), (0.0, 0.0, 1.0), 27.5),
        extrude(outline(polyline([(238.5, 487.6118164), (-238.5, 487.6118164), (-238.5, 491.1118408), (238.5, 491.1118408), (238.5, 487.6118164)])), frame((0.0, 0.0, 384.0), z_axis=(0.0, 0.0, 1.0), x_axis=(1.0, 0.0, 0.0)), (0.0, 0.0, 1.0), 27.5),
        extrude(outline(polyline([(130.5000244, 149.7947388), (115.5000244, 149.7947388), (115.5000244, 154.5), (119.5000244, 158.5), (126.5000244, 158.5), (130.5000244, 154.5), (130.5000244, 149.7947388)])), frame((-216.555896, 0.0, 0.0), z_axis=(1.0, 0.0, 0.0), x_axis=(0.0, 1.0, 0.0)), (0.0, 0.0, 1.0), 433.111792),
        extrude(outline(polyline([(192.5000244, 149.7947388), (177.5000244, 149.7947388), (177.5000244, 154.5), (181.5000244, 158.5), (188.5000244, 158.5), (192.5000244, 154.5), (192.5000244, 149.7947388)])), frame((-216.555896, 0.0, 0.0), z_axis=(1.0, 0.0, 0.0), x_axis=(0.0, 1.0, 0.0)), (0.0, 0.0, 1.0), 433.111792),
        extrude(outline(polyline([(254.5000244, 149.7947388), (239.5000244, 149.7947388), (239.5000244, 154.5), (243.5000244, 158.5), (250.5000244, 158.5), (254.5000244, 154.5), (254.5000244, 149.7947388)])), frame((-216.555896, 0.0, 0.0), z_axis=(1.0, 0.0, 0.0), x_axis=(0.0, 1.0, 0.0)), (0.0, 0.0, 1.0), 433.111792),
        extrude(outline(polyline([(301.5000244, 149.7947388), (301.5000244, 154.5), (305.5000244, 158.5), (312.5000244, 158.5), (316.5000244, 154.5), (316.5000244, 149.7947388), (301.5000244, 149.7947388)])), frame((-216.555896, 0.0, 0.0), z_axis=(1.0, 0.0, 0.0), x_axis=(0.0, 1.0, 0.0)), (0.0, 0.0, 1.0), 433.111792),
        extrude(outline(polyline([(24.4663125, 51.0000244), (-24.4663125, 51.0000244), (-24.4663125, 80.5000244), (24.4663125, 80.5000244), (24.4663125, 51.0000244)])), frame((0.0, 0.0, 676.4573822), z_axis=(0.0, 0.0, 1.0), x_axis=(1.0, 0.0, 0.0)), (0.0, 0.0, 1.0), 36.4124668),
        extrude(outline(polyline([(238.5, 54.5000244), (219.7422474, 54.5000244), (219.7422474, 487.6118164), (238.5, 487.6118164), (238.5, 54.5000244)])), frame((0.0, 0.0, 384.0), z_axis=(0.0, 0.0, 1.0), x_axis=(1.0, 0.0, 0.0)), (0.0, 0.0, 1.0), 27.5),
        extrude(outline(polyline([(-219.7422474, 54.5000244), (-238.5, 54.5000244), (-238.5, 487.6118164), (-219.7422474, 487.6118164), (-219.7422474, 54.5000244)])), frame((0.0, 0.0, 384.0), z_axis=(0.0, 0.0, 1.0), x_axis=(1.0, 0.0, 0.0)), (0.0, 0.0, 1.0), 27.5),
        extrude(outline(polyline([(238.5, 54.5000244), (219.7422474, 54.5000244), (219.7422474, 487.6118164), (238.5, 487.6118164), (238.5, 54.5000244)])), frame((0.0, 0.0, 474.5), z_axis=(0.0, 0.0, 1.0), x_axis=(1.0, 0.0, 0.0)), (0.0, 0.0, 1.0), 27.5),
        extrude(outline(polyline([(-219.7422474, 54.5000244), (-238.5, 54.5000244), (-238.5, 487.6118164), (-219.7422474, 487.6118164), (-219.7422474, 54.5000244)])), frame((0.0, 0.0, 474.5), z_axis=(0.0, 0.0, 1.0), x_axis=(1.0, 0.0, 0.0)), (0.0, 0.0, 1.0), 27.5),
        extrude(outline(polyline([(238.5, 54.5000244), (219.7422474, 54.5000244), (219.7422474, 487.6118164), (238.5, 487.6118164), (238.5, 54.5000244)])), frame((0.0, 0.0, 564.0), z_axis=(0.0, 0.0, 1.0), x_axis=(1.0, 0.0, 0.0)), (0.0, 0.0, 1.0), 27.5),
        extrude(outline(polyline([(-219.7422474, 54.5000244), (-238.5, 54.5000244), (-238.5, 487.6118164), (-219.7422474, 487.6118164), (-219.7422474, 54.5000244)])), frame((0.0, 0.0, 564.0), z_axis=(0.0, 0.0, 1.0), x_axis=(1.0, 0.0, 0.0)), (0.0, 0.0, 1.0), 27.5),
        extrude(outline(polyline([(-219.7422474, 54.5000244), (-238.5, 54.5000244), (-238.5, 487.6118164), (-219.7422474, 487.6118164), (-219.7422474, 54.5000244)])), frame((0.0, 0.0, 235.0), z_axis=(0.0, 0.0, 1.0), x_axis=(1.0, 0.0, 0.0)), (0.0, 0.0, 1.0), 27.5),
        extrude(outline(polyline([(238.5, 54.5000244), (219.7422474, 54.5000244), (219.7422474, 487.6118164), (238.5, 487.6118164), (238.5, 54.5000244)])), frame((0.0, 0.0, 235.0), z_axis=(0.0, 0.0, 1.0), x_axis=(1.0, 0.0, 0.0)), (0.0, 0.0, 1.0), 27.5),
        extrude(outline(polyline([(298.0, 34.0937347), (-298.0, 34.0937347), (-298.0, 44.0), (298.0, 44.0), (298.0, 34.0937347)])), frame((0.0, 0.0, 768.7051238), z_axis=(0.0, 0.0, 1.0), x_axis=(1.0, 0.0, 0.0)), (0.0, 0.0, 1.0), 48.9938508),
        faceted_brep([(-298.5, 573.5, 137.8999939), (-298.5, 573.5, 117.6051112), (-298.5, 561.0, 105.1051112), (-298.5, 561.0, 0.0), (-298.5, 161.2567793, 0.0), (-298.5, 152.9391747, 8.3176046), (-298.5, 100.0, 8.3176046), (-298.5, 100.0, 60.7725754), (-298.5, 79.0216446, 60.7725754), (-298.5, 79.0216446, 101.8184894), (-298.5, 44.0, 101.8184894), (-298.5, 44.0, 137.8999939), (298.5, 573.5, 137.8999939), (298.5, 44.0, 137.8999939), (298.5, 44.0, 101.8184894), (298.5, 79.0216446, 101.8184894), (298.5, 79.0216446, 60.7725754), (298.5, 100.0, 60.7725754), (298.5, 100.0, 8.3176046), (298.5, 152.9391747, 8.3176046), (298.5, 161.2567793, 0.0), (298.5, 561.0, 0.0), (298.5, 561.0, 105.1051112), (298.5, 573.5, 117.6051112), (296.7000122, 487.2596389, 0.0), (256.5957336, 487.2596389, 0.0), (256.5957336, 422.5975098, 0.0), (296.7000122, 422.5975098, 0.0), (-296.7000122, 487.2596389, 0.0), (-296.7000122, 422.5975098, 0.0), (-256.5957336, 422.5975098, 0.0), (-256.5957336, 487.2596389, 0.0), (296.7000122, 487.2596389, 8.7371401), (296.7000122, 422.5975098, 8.7371401), (256.5957336, 422.5975098, 8.7371401), (256.5957336, 487.2596389, 8.7371401), (-296.7000122, 487.2596389, 8.7371401), (-256.5957336, 487.2596389, 8.7371401), (-256.5957336, 422.5975098, 8.7371401), (-296.7000122, 422.5975098, 8.7371401)], [[[0, 1, 2, 3, 4, 5, 6, 7, 8, 9, 10, 11]], [[12, 13, 14, 15, 16, 17, 18, 19, 20, 21, 22, 23]], [[0, 11, 13, 12]], [[11, 10, 14, 13]], [[10, 9, 15, 14]], [[9, 8, 16, 15]], [[8, 7, 17, 16]], [[7, 6, 18, 17]], [[6, 5, 19, 18]], [[5, 4, 20, 19]], [[4, 3, 21, 20], [24, 25, 26, 27], [28, 29, 30, 31]], [[3, 2, 22, 21]], [[2, 1, 23, 22]], [[1, 0, 12, 23]], [[32, 33, 34, 35]], [[36, 37, 38, 39]], [[32, 35, 25, 24]], [[35, 34, 26, 25]], [[34, 33, 27, 26]], [[33, 32, 24, 27]], [[36, 39, 29, 28]], [[39, 38, 30, 29]], [[38, 37, 31, 30]], [[37, 36, 28, 31]]]),
        faceted_brep([(298.5, 44.0, 819.0), (298.5, 44.0, 137.8999939), (298.5, 579.6, 137.8999939), (298.5, 579.6, 819.0), (-298.5, 44.0, 819.0), (-298.5, 579.6, 819.0), (-298.5, 579.6, 137.8999939), (-298.5, 44.0, 137.8999939), (250.0, 44.0, 719.0), (250.0, 44.0, 150.0), (-250.0, 44.0, 150.0), (-250.0, 44.0, 719.0), (250.0, 534.2638012, 150.0), (250.0, 534.2638012, 719.0), (-250.0, 534.2638012, 719.0), (-250.0, 534.2638012, 150.0)], [[[0, 1, 2, 3]], [[4, 5, 6, 7]], [[1, 0, 4, 7], [8, 9, 10, 11]], [[2, 1, 7, 6]], [[3, 2, 6, 5]], [[0, 3, 5, 4]], [[12, 13, 14, 15]], [[13, 12, 9, 8]], [[14, 13, 8, 11]], [[15, 14, 11, 10]], [[12, 15, 10, 9]]]),
        extrude(outline(polyline([(250.0, 534.2638012), (250.0, 362.7), (-250.0, 362.7), (-250.0, 534.2638012), (250.0, 534.2638012)])), frame((0.0, 0.0, 150.0), z_axis=(0.0, 0.0, 1.0), x_axis=(1.0, 0.0, 0.0)), (0.0, 0.0, 1.0), 71.8999939),
        extrude(outline(composite_curve([segment(trimmed(circle_curve(frame_2d((-270.8532135, 136.0)), 15.7049948), [point((-286.5582083, 136.0))], [point((-255.1482187, 136.0))], False, "CARTESIAN"), True, "CONTINUOUS"), segment(trimmed(circle_curve(frame_2d((-270.8532135, 136.0)), 15.7049948), [point((-255.1482187, 136.0))], [point((-286.5582083, 136.0))], False, "CARTESIAN"), True, "CONTINUOUS")], self_intersect=False)), origin_with_axes(), (0.0, 0.0, 1.0), 8.3176046),
        extrude(outline(composite_curve([segment(trimmed(circle_curve(frame_2d((270.8532135, 136.0)), 15.7049948), [point((286.5582083, 136.0))], [point((255.1482187, 136.0))], False, "CARTESIAN"), True, "CONTINUOUS"), segment(trimmed(circle_curve(frame_2d((270.8532135, 136.0)), 15.7049948), [point((255.1482187, 136.0))], [point((286.5582083, 136.0))], False, "CARTESIAN"), True, "CONTINUOUS")], self_intersect=False)), origin_with_axes(), (0.0, 0.0, 1.0), 8.3176046),
        extrude(outline(composite_curve([segment(trimmed(circle_curve(frame_2d((-275.822369, 461.1)), 16.0), [point((-291.822369, 461.1))], [point((-259.822369, 461.1))], False, "CARTESIAN"), True, "CONTINUOUS"), segment(trimmed(circle_curve(frame_2d((-275.822369, 461.1)), 16.0), [point((-259.822369, 461.1))], [point((-291.822369, 461.1))], False, "CARTESIAN"), True, "CONTINUOUS")], self_intersect=False)), origin_with_axes(), (0.0, 0.0, 1.0), 8.3176046),
        extrude(outline(composite_curve([segment(trimmed(circle_curve(frame_2d((275.822369, 461.1)), 16.0), [point((259.822369, 461.1))], [point((291.822369, 461.1))], False, "CARTESIAN"), True, "CONTINUOUS"), segment(trimmed(circle_curve(frame_2d((275.822369, 461.1)), 16.0), [point((291.822369, 461.1))], [point((259.822369, 461.1))], False, "CARTESIAN"), True, "CONTINUOUS")], self_intersect=False)), origin_with_axes(), (0.0, 0.0, 1.0), 8.3176046),
        extrude(outline(composite_curve([segment(trimmed(circle_curve(frame_2d((144.2460785, 224.8152695)), 8.0), [point((144.2460785, 216.8152695))], [point((144.2460785, 232.8152695))], False, "CARTESIAN"), True, "CONTINUOUS"), segment(trimmed(circle_curve(frame_2d((144.2460785, 224.8152695)), 8.0), [point((144.2460785, 232.8152695))], [point((144.2460785, 216.8152695))], False, "CARTESIAN"), True, "CONTINUOUS")], self_intersect=False)), frame((0.0, 579.6, 0.0), z_axis=(0.0, 1.0, 0.0), x_axis=(0.0, 0.0, 1.0)), (0.0, 0.0, 1.0), 30.0),
        extrude(outline(polyline([(140.2460785, 230.7170777), (148.2825833, 230.7170777), (148.2825833, 224.9408399), (147.2780202, 224.9408399), (147.2780202, 229.7125146), (144.8921828, 229.7125146), (144.8921828, 225.1919806), (143.8876197, 225.1919806), (143.8876197, 229.7125146), (141.2506416, 229.7125146), (141.2506416, 224.8152695), (140.2460785, 224.8152695), (140.2460785, 230.7170777)])), frame((0.0, 609.6, 0.0), z_axis=(0.0, 1.0, 0.0), x_axis=(0.0, 0.0, 1.0)), (0.0, 0.0, 1.0), 1.0),
        extrude(outline(polyline([(140.2460785, 223.3084248), (148.2825833, 223.3084248), (148.2825833, 222.3038617), (141.2506416, 222.3038617), (141.2506416, 218.2856093), (140.2460785, 218.2856093), (140.2460785, 223.3084248)])), frame((0.0, 609.6, 0.0), z_axis=(0.0, 1.0, 0.0), x_axis=(0.0, 0.0, 1.0)), (0.0, 0.0, 1.0), 1.0),
        faceted_brep([(297.0, 0.0, 762.0), (-297.0, 0.0, 762.0), (-297.0, 0.0, 100.0), (297.0, 0.0, 100.0), (-238.0, 0.0, 670.0), (238.0, 0.0, 670.0), (238.0, 0.0, 198.0), (-238.0, 0.0, 198.0), (297.0, 32.0, 100.0), (-297.0, 32.0, 100.0), (-297.0, 32.0, 762.0), (297.0, 32.0, 762.0), (297.0, 32.0, 145.5520399), (190.2289267, 32.0, 145.5520399), (190.2289267, 32.0, 100.9715583), (297.0, 32.0, 100.9715583), (238.0, 32.0, 670.0), (-238.0, 32.0, 670.0), (-238.0, 32.0, 198.0), (238.0, 32.0, 198.0), (297.0, 10.6130013, 100.9715583), (297.0, 10.6130013, 145.5520399), (190.2289267, 10.6130013, 145.5520399), (190.2289267, 10.6130013, 100.9715583)], [[[0, 1, 2, 3], [4, 5, 6, 7]], [[8, 9, 10, 11, 12, 13, 14, 15], [16, 17, 18, 19]], [[1, 0, 11, 10]], [[2, 1, 10, 9]], [[3, 2, 9, 8]], [[0, 3, 8, 15, 20, 21, 12, 11]], [[16, 5, 4, 17]], [[17, 4, 7, 18]], [[18, 7, 6, 19]], [[5, 16, 19, 6]], [[21, 22, 13, 12]], [[14, 23, 20, 15]], [[23, 22, 21, 20]], [[22, 23, 14, 13]]]),
        extrude(outline(polyline([(764.5, 285.0), (764.5, -285.0), (148.5030441, -285.0), (148.5030441, 285.0), (764.5, 285.0)]), holes=[polyline([(670.0, -238.0), (670.0, 238.0), (198.0, 238.0), (198.0, -238.0), (670.0, -238.0)])]), frame((0.0, 32.0, 0.0), z_axis=(0.0, 1.0, 0.0), x_axis=(0.0, 0.0, 1.0)), (0.0, 0.0, 1.0), 12.0),
        extrude(outline(polyline([(297.0, 0.0), (297.0, -4.3999998), (-297.0, -4.3999998), (-297.0, 0.0), (297.0, 0.0)])), frame((0.0, 0.0, 787.8718872), z_axis=(0.0, 0.0, 1.0), x_axis=(1.0, 0.0, 0.0)), (0.0, 0.0, 1.0), 28.4282238),
        extrude(outline(polyline([(31.449995, 816.3006898), (31.449995, 762.0), (0.0, 762.0), (0.0, 764.3706666), (25.2610212, 764.3706666), (25.2610212, 799.0085449), (3.0130013, 799.0085449), (3.0130013, 787.161485), (0.0, 787.161485), (0.0, 816.3006898), (31.449995, 816.3006898)])), frame((-297.0, 0.0, 0.0), z_axis=(1.0, 0.0, 0.0), x_axis=(0.0, 1.0, 0.0)), (0.0, 0.0, 1.0), 594.0),
        extrude(outline(polyline([(238.0, 0.0), (-238.0, 0.0), (-238.0, 32.0), (238.0, 32.0), (238.0, 0.0)])), frame((0.0, 0.0, 197.9069346), z_axis=(0.0, 0.0, 1.0), x_axis=(1.0, 0.0, 0.0)), (0.0, 0.0, 1.0), 472.0930654),
        extrude(outline(polyline([(298.5, 10.6130013), (190.2289267, 10.6130013), (190.2289267, 44.0), (298.5, 44.0), (298.5, 10.6130013)])), frame((0.0, 0.0, 100.0), z_axis=(0.0, 0.0, 1.0), x_axis=(1.0, 0.0, 0.0)), (0.0, 0.0, 1.0), 41.0),
    ])


if __name__ == "__main__":
    model = new_model("IFC4")
    model_context = context("Model", 3, world=origin())
    ifc_project = project(units=[si_unit("LENGTHUNIT", "METRE", prefix="MILLI")], contexts=[model_context])
    site = spatial("IfcSite", under=ifc_project)
    building = spatial("IfcBuilding", under=site)
    placement = place(None, origin())
    specialty_equipment_shape = specialty_equipment_1184f20f(model_context)
    element("IfcBuildingElementProxy", 1, Name="Specialty Equipment", at=placement, inside=building, context=model_context, shape_type="MappedRepresentation", body=[
        mapped(specialty_equipment_shape, transform((0.0, 0.0, 0.0), x_axis=(1.0, 0.0, 0.0), y_axis=(0.0, 1.0, 0.0), z_axis=(0.0, 0.0, 1.0))),
    ])
    save(model, "model.ifc")
